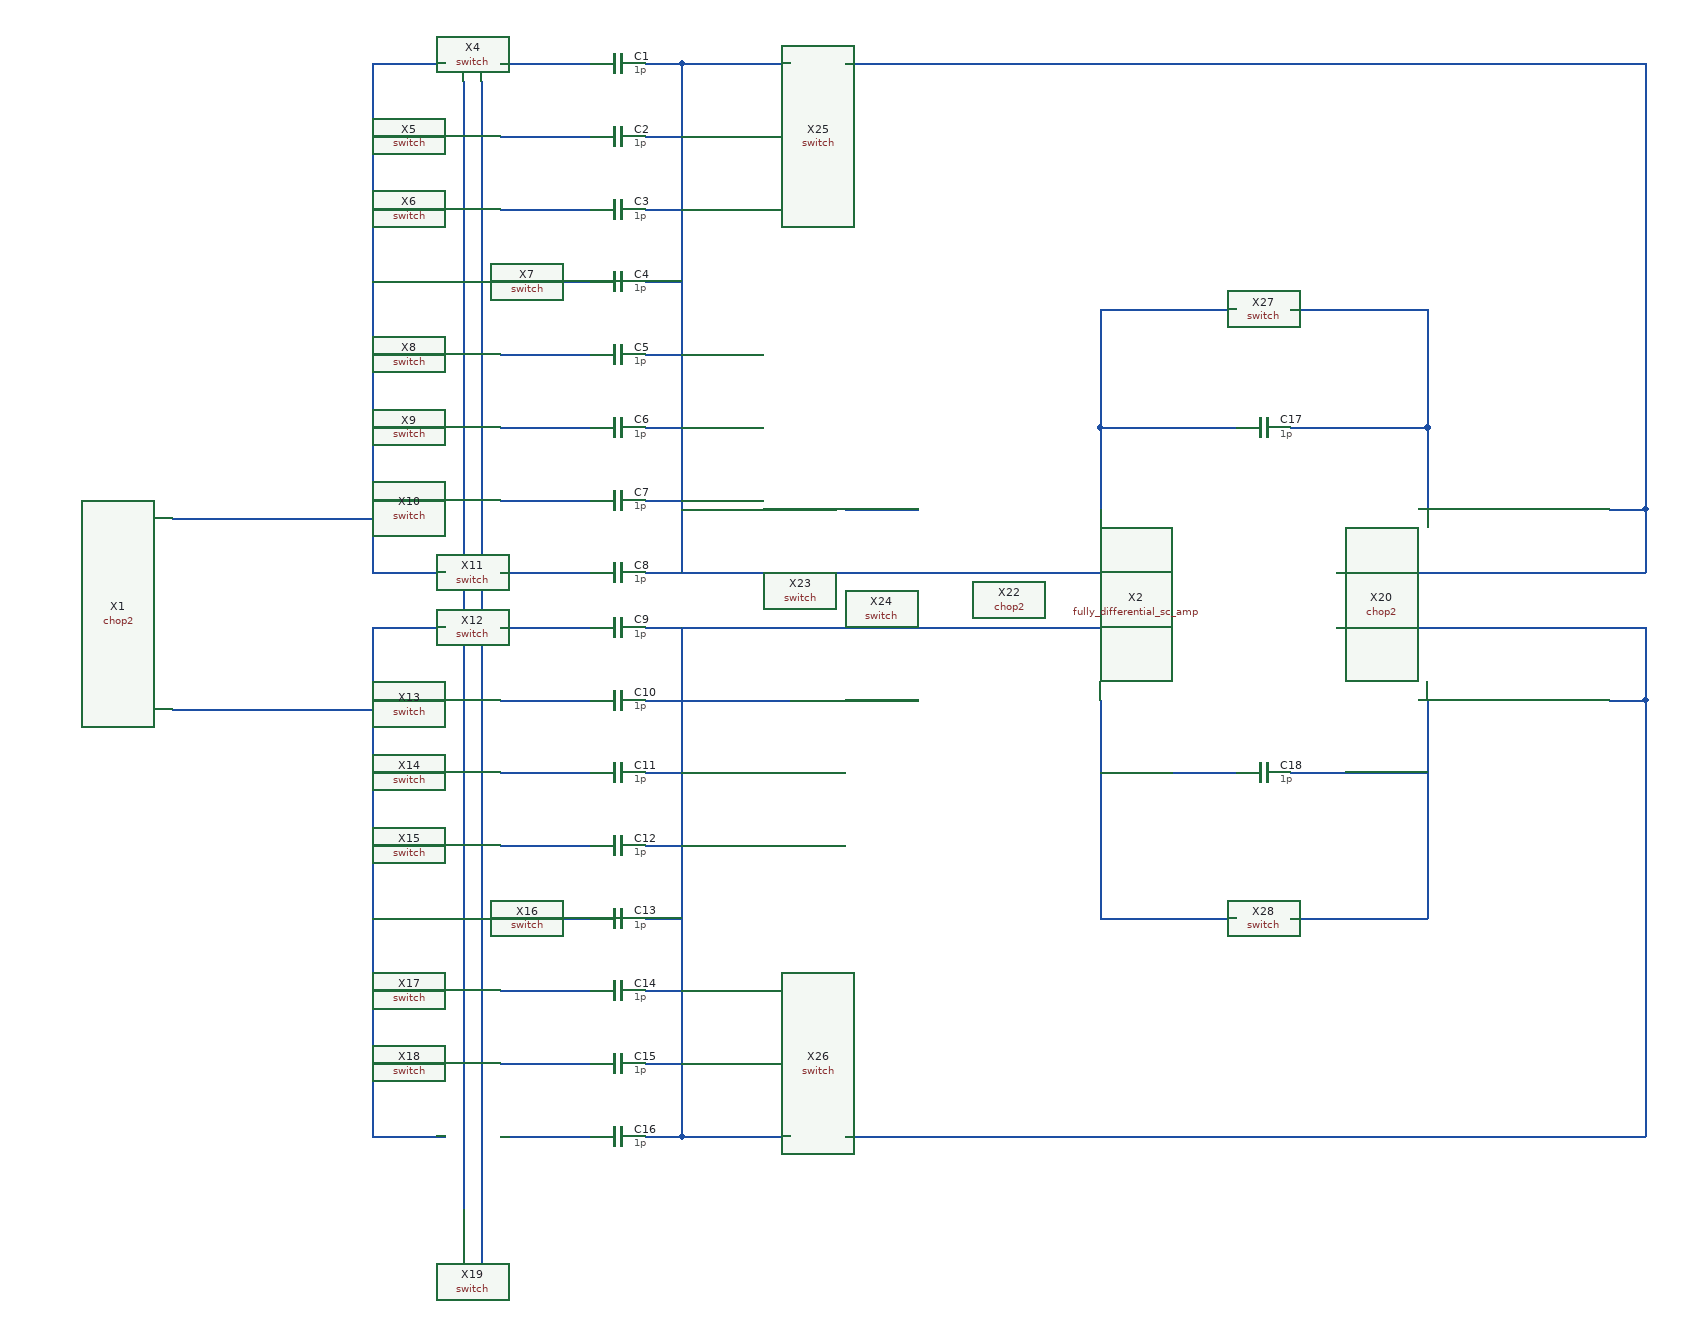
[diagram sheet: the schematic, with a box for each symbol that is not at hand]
v {xschem version=2.9.9 file_version=1.2 }
G {}
K {}
V {}
S {}
E {}
N 280 -680 500 -680 { lab=#net1}
N 500 -620 580 -620 { lab=#net1}
N 500 -1180 500 -620 { lab=#net1}
N 500 -1180 580 -1180 { lab=#net1}
N 500 -1100 580 -1100 { lab=#net1}
N 500 -1020 580 -1020 { lab=#net1}
N 500 -940 580 -940 { lab=#net1}
N 500 -860 580 -860 { lab=#net1}
N 500 -780 580 -780 { lab=#net1}
N 500 -700 580 -700 { lab=#net1}
N 500 0 580 0 { lab=#net2}
N 500 -560 500 0 { lab=#net2}
N 500 -560 580 -560 { lab=#net2}
N 500 -480 580 -480 { lab=#net2}
N 500 -400 580 -400 { lab=#net2}
N 500 -320 580 -320 { lab=#net2}
N 500 -240 580 -240 { lab=#net2}
N 500 -160 580 -160 { lab=#net2}
N 500 -80 580 -80 { lab=#net2}
N 280 -470 500 -470 { lab=#net2}
N 640 -0 740 0 { lab=#net3}
N 640 -80 740 -80 { lab=#net4}
N 640 -160 740 -160 { lab=#net5}
N 640 -240 740 -240 { lab=#net6}
N 640 -320 740 -320 { lab=#net7}
N 640 -400 740 -400 { lab=#net8}
N 640 -480 740 -480 { lab=#net9}
N 640 -560 740 -560 { lab=#net10}
N 640 -620 740 -620 { lab=#net11}
N 640 -700 740 -700 { lab=#net12}
N 640 -780 740 -780 { lab=#net13}
N 640 -860 740 -860 { lab=#net14}
N 640 -940 740 -940 { lab=#net15}
N 640 -1020 740 -1020 { lab=#net16}
N 640 -1100 740 -1100 { lab=#net17}
N 640 -1180 740 -1180 { lab=#net18}
N 600 -1160 600 80 { lab=#net19}
N 620 -1160 620 140 { lab=#net20}
N 800 -620 1380 -620 { lab=#net21}
N 800 -560 1380 -560 { lab=#net22}
N 800 -1180 840 -1180 { lab=#net21}
N 840 -1180 840 -620 { lab=#net21}
N 800 -1100 840 -1100 { lab=#net21}
N 800 -1020 840 -1020 { lab=#net21}
N 800 -940 840 -940 { lab=#net21}
N 800 -860 840 -860 { lab=#net21}
N 800 -780 840 -780 { lab=#net21}
N 800 -700 840 -700 { lab=#net21}
N 800 -480 840 -480 { lab=#net22}
N 800 -400 840 -400 { lab=#net22}
N 800 -320 840 -320 { lab=#net22}
N 800 -240 840 -240 { lab=#net22}
N 800 -160 840 -160 { lab=#net22}
N 800 -80 840 -80 { lab=#net22}
N 800 0 840 0 { lab=#net22}
N 840 -560 840 -0 { lab=#net22}
N 840 -1180 960 -1180 { lab=#net21}
N 840 -690 960 -690 { lab=#net21}
N 1020 -690 1100 -690 { lab=#net23}
N 840 0 960 -0 { lab=#net22}
N 1300 -780 1450 -780 { lab=#net24}
N 1510 -780 1660 -780 { lab=#net25}
N 1660 -780 1660 -690 { lab=#net25}
N 1300 -400 1450 -400 { lab=#net26}
N 1510 -400 1660 -400 { lab=#net27}
N 1660 -480 1660 -420 { lab=#net27}
N 1300 -910 1450 -910 { lab=#net24}
N 1300 -910 1300 -780 { lab=#net24}
N 1510 -910 1660 -910 { lab=#net25}
N 1660 -910 1660 -780 { lab=#net25}
N 1510 -240 1660 -240 { lab=#net27}
N 1660 -420 1660 -240 { lab=#net27}
N 1300 -420 1300 -240 { lab=#net26}
N 1300 -240 1450 -240 { lab=#net26}
N 1300 -780 1300 -690 { lab=#net24}
N 1300 -480 1300 -420 { lab=#net26}
N 840 -480 960 -480 { lab=#net22}
N 1020 -480 1100 -480 { lab=#net28}
N 1860 -690 1900 -690 { lab=#net29}
N 1900 -1180 1900 -690 { lab=#net29}
N 1020 -1180 1900 -1180 { lab=#net29}
N 1020 -0 1900 -0 { lab=#net30}
N 1900 -480 1900 -0 { lab=#net30}
N 1860 -480 1900 -480 { lab=#net30}
N 1560 -620 1900 -620 { lab=#net29}
N 1900 -690 1900 -620 { lab=#net29}
N 1560 -560 1900 -560 { lab=#net30}
N 1900 -560 1900 -480 { lab=#net30}
C {/home/madvlsi/Documents/MADVLSI-Final_Project/schematic/chop2.sym} 180 -580 0 0 {name=X1 Wp=1 Lp=0.15 WW=1 LL=0.15}
C {/home/madvlsi/Documents/MADVLSI-Final_Project/schematic/fully_differential_sc_amp.sym} 1350 -590 0 0 {name=X2}
C {madvlsi/capacitor.sym} 770 -1180 1 0 {name=C1
value=1p
m=1}
C {madvlsi/capacitor.sym} 770 -1100 1 0 {name=C2
value=1p
m=1}
C {madvlsi/capacitor.sym} 770 -1020 1 0 {name=C3
value=1p
m=1}
C {madvlsi/capacitor.sym} 770 -940 1 0 {name=C4
value=1p
m=1}
C {madvlsi/capacitor.sym} 770 -860 1 0 {name=C5
value=1p
m=1}
C {madvlsi/capacitor.sym} 770 -780 1 0 {name=C6
value=1p
m=1}
C {madvlsi/capacitor.sym} 770 -700 1 0 {name=C7
value=1p
m=1}
C {madvlsi/capacitor.sym} 770 -620 1 0 {name=C8
value=1p
m=1}
C {madvlsi/capacitor.sym} 770 -560 1 0 {name=C9
value=1p
m=1}
C {madvlsi/capacitor.sym} 770 -480 1 0 {name=C10
value=1p
m=1}
C {madvlsi/capacitor.sym} 770 -400 1 0 {name=C11
value=1p
m=1}
C {madvlsi/capacitor.sym} 770 -320 1 0 {name=C12
value=1p
m=1}
C {madvlsi/capacitor.sym} 770 -240 1 0 {name=C13
value=1p
m=1}
C {madvlsi/capacitor.sym} 770 -160 1 0 {name=C14
value=1p
m=1}
C {madvlsi/capacitor.sym} 770 -80 1 0 {name=C15
value=1p
m=1}
C {madvlsi/capacitor.sym} 770 0 1 0 {name=C16
value=1p
m=1}
C {/home/madvlsi/Documents/MADVLSI-Final_Project/schematic/switch.sym} 610 -1180 0 0 {name=X4 Wp=1 Lp=0.15 WW=1 LL=0.15}
C {/home/madvlsi/Documents/MADVLSI-Final_Project/schematic/switch.sym} 610 -1100 0 0 {name=X5 Wp=1 Lp=0.15 WW=1 LL=0.15}
C {/home/madvlsi/Documents/MADVLSI-Final_Project/schematic/switch.sym} 610 -1020 0 0 {name=X6 Wp=1 Lp=0.15 WW=1 LL=0.15}
C {/home/madvlsi/Documents/MADVLSI-Final_Project/schematic/switch.sym} 610 -940 0 0 {name=X7 Wp=1 Lp=0.15 WW=1 LL=0.15}
C {/home/madvlsi/Documents/MADVLSI-Final_Project/schematic/switch.sym} 610 -860 0 0 {name=X8 Wp=1 Lp=0.15 WW=1 LL=0.15}
C {/home/madvlsi/Documents/MADVLSI-Final_Project/schematic/switch.sym} 610 -780 0 0 {name=X9 Wp=1 Lp=0.15 WW=1 LL=0.15}
C {/home/madvlsi/Documents/MADVLSI-Final_Project/schematic/switch.sym} 610 -700 0 0 {name=X10 Wp=1 Lp=0.15 WW=1 LL=0.15}
C {/home/madvlsi/Documents/MADVLSI-Final_Project/schematic/switch.sym} 610 -620 0 0 {name=X11 Wp=1 Lp=0.15 WW=1 LL=0.15}
C {/home/madvlsi/Documents/MADVLSI-Final_Project/schematic/switch.sym} 610 -560 0 0 {name=X12 Wp=1 Lp=0.15 WW=1 LL=0.15}
C {/home/madvlsi/Documents/MADVLSI-Final_Project/schematic/switch.sym} 610 -480 0 0 {name=X13 Wp=1 Lp=0.15 WW=1 LL=0.15}
C {/home/madvlsi/Documents/MADVLSI-Final_Project/schematic/switch.sym} 610 -400 0 0 {name=X14 Wp=1 Lp=0.15 WW=1 LL=0.15}
C {/home/madvlsi/Documents/MADVLSI-Final_Project/schematic/switch.sym} 610 -320 0 0 {name=X15 Wp=1 Lp=0.15 WW=1 LL=0.15}
C {/home/madvlsi/Documents/MADVLSI-Final_Project/schematic/switch.sym} 610 -240 0 0 {name=X16 Wp=1 Lp=0.15 WW=1 LL=0.15}
C {/home/madvlsi/Documents/MADVLSI-Final_Project/schematic/switch.sym} 610 -160 0 0 {name=X17 Wp=1 Lp=0.15 WW=1 LL=0.15}
C {/home/madvlsi/Documents/MADVLSI-Final_Project/schematic/switch.sym} 610 -80 0 0 {name=X18 Wp=1 Lp=0.15 WW=1 LL=0.15}
C {/home/madvlsi/Documents/MADVLSI-Final_Project/schematic/switch.sym} 610 0 0 0 {name=X19 Wp=1 Lp=0.15 WW=1 LL=0.15}
C {madvlsi/capacitor.sym} 1480 -780 1 0 {name=C17
value=1p
m=1}
C {madvlsi/capacitor.sym} 1480 -400 1 0 {name=C18
value=1p
m=1}
C {/home/madvlsi/Documents/MADVLSI-Final_Project/schematic/chop2.sym} 1760 -590 0 0 {name=X20 Wp=1 Lp=0.15 WW=1 LL=0.15}
C {/home/madvlsi/Documents/MADVLSI-Final_Project/schematic/chop2.sym} 1200 -590 0 0 {name=X22 Wp=1 Lp=0.15 WW=1 LL=0.15}
C {/home/madvlsi/Documents/MADVLSI-Final_Project/schematic/switch.sym} 990 -690 0 0 {name=X23 Wp=1 Lp=0.15 WW=1 LL=0.15}
C {/home/madvlsi/Documents/MADVLSI-Final_Project/schematic/switch.sym} 990 -480 0 0 {name=X24 Wp=1 Lp=0.15 WW=1 LL=0.15}
C {/home/madvlsi/Documents/MADVLSI-Final_Project/schematic/switch.sym} 990 -1180 0 0 {name=X25 Wp=1 Lp=0.15 WW=1 LL=0.15}
C {/home/madvlsi/Documents/MADVLSI-Final_Project/schematic/switch.sym} 990 0 0 0 {name=X26 Wp=1 Lp=0.15 WW=1 LL=0.15}
C {/home/madvlsi/Documents/MADVLSI-Final_Project/schematic/switch.sym} 1480 -910 0 0 {name=X27 Wp=1 Lp=0.15 WW=1 LL=0.15}
C {/home/madvlsi/Documents/MADVLSI-Final_Project/schematic/switch.sym} 1480 -240 0 0 {name=X28 Wp=1 Lp=0.15 WW=1 LL=0.15}
